VERSION 5.8 ;
BUSBITCHARS "[]" ;
DIVIDERCHAR "/" ;
UNITS
    DATABASE MICRONS 1000 ;
END UNITS

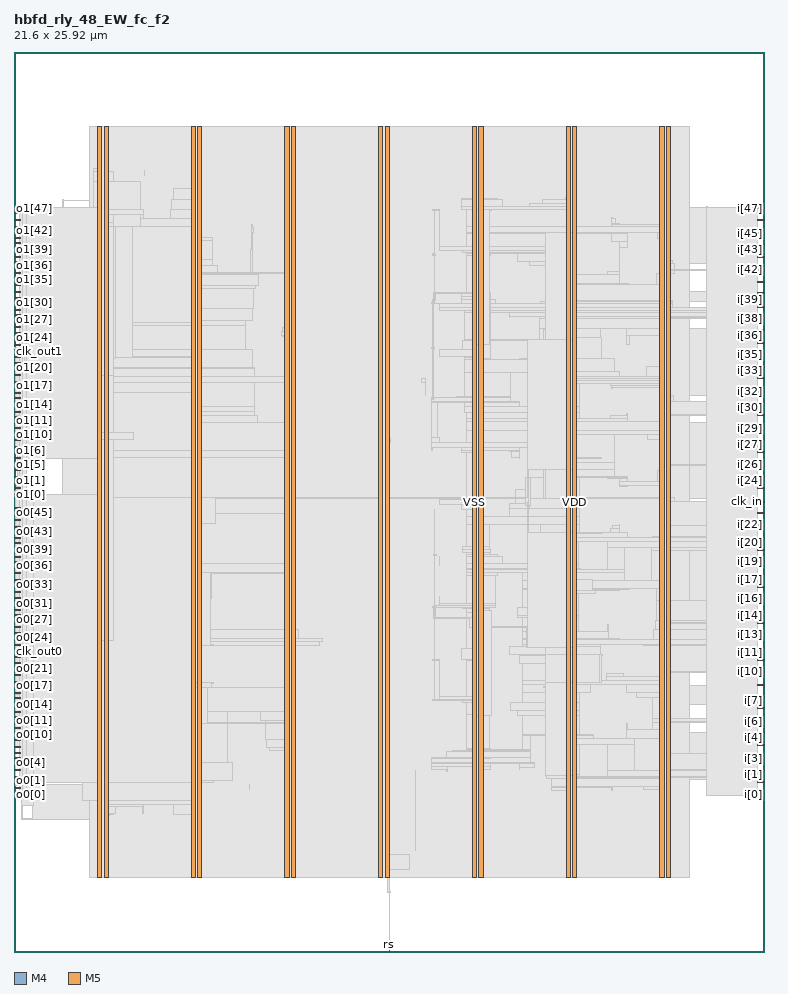
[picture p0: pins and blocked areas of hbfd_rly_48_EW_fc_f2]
MACRO hbfd_rly_48_EW_fc_f2
  FOREIGN hbfd_rly_48_EW_fc_f2 0 0 ;
  CLASS BLOCK ;
  SIZE 21.6 BY 25.92 ;
  PIN clk_in
    DIRECTION INPUT ;
    USE SIGNAL ;
    PORT
      LAYER M4 ;
        RECT  21.408 12.96 21.6 12.984 ;
    END
  END clk_in
  PIN clk_out0
    DIRECTION OUTPUT ;
    USE SIGNAL ;
    PORT
      LAYER M4 ;
        RECT  0 8.64 0.192 8.664 ;
    END
  END clk_out0
  PIN clk_out1
    DIRECTION OUTPUT ;
    USE SIGNAL ;
    PORT
      LAYER M4 ;
        RECT  0 17.28 0.192 17.304 ;
    END
  END clk_out1
  PIN i[0]
    DIRECTION INPUT ;
    USE SIGNAL ;
    PORT
      LAYER M4 ;
        RECT  21.408 4.512 21.6 4.536 ;
    END
  END i[0]
  PIN i[10]
    DIRECTION INPUT ;
    USE SIGNAL ;
    PORT
      LAYER M4 ;
        RECT  21.408 8.064 21.6 8.088 ;
    END
  END i[10]
  PIN i[11]
    DIRECTION INPUT ;
    USE SIGNAL ;
    PORT
      LAYER M4 ;
        RECT  21.408 8.4 21.6 8.424 ;
    END
  END i[11]
  PIN i[12]
    DIRECTION INPUT ;
    USE SIGNAL ;
    PORT
      LAYER M4 ;
        RECT  21.408 8.736 21.6 8.76 ;
    END
  END i[12]
  PIN i[13]
    DIRECTION INPUT ;
    USE SIGNAL ;
    PORT
      LAYER M4 ;
        RECT  21.408 9.12 21.6 9.144 ;
    END
  END i[13]
  PIN i[14]
    DIRECTION INPUT ;
    USE SIGNAL ;
    PORT
      LAYER M4 ;
        RECT  21.408 9.456 21.6 9.48 ;
    END
  END i[14]
  PIN i[15]
    DIRECTION INPUT ;
    USE SIGNAL ;
    PORT
      LAYER M4 ;
        RECT  21.408 9.792 21.6 9.816 ;
    END
  END i[15]
  PIN i[16]
    DIRECTION INPUT ;
    USE SIGNAL ;
    PORT
      LAYER M4 ;
        RECT  21.408 10.176 21.6 10.2 ;
    END
  END i[16]
  PIN i[17]
    DIRECTION INPUT ;
    USE SIGNAL ;
    PORT
      LAYER M4 ;
        RECT  21.408 10.512 21.6 10.536 ;
    END
  END i[17]
  PIN i[18]
    DIRECTION INPUT ;
    USE SIGNAL ;
    PORT
      LAYER M4 ;
        RECT  21.408 10.848 21.6 10.872 ;
    END
  END i[18]
  PIN i[19]
    DIRECTION INPUT ;
    USE SIGNAL ;
    PORT
      LAYER M4 ;
        RECT  21.408 11.232 21.6 11.256 ;
    END
  END i[19]
  PIN i[1]
    DIRECTION INPUT ;
    USE SIGNAL ;
    PORT
      LAYER M4 ;
        RECT  21.408 4.896 21.6 4.92 ;
    END
  END i[1]
  PIN i[20]
    DIRECTION INPUT ;
    USE SIGNAL ;
    PORT
      LAYER M4 ;
        RECT  21.408 11.568 21.6 11.592 ;
    END
  END i[20]
  PIN i[21]
    DIRECTION INPUT ;
    USE SIGNAL ;
    PORT
      LAYER M4 ;
        RECT  21.408 11.904 21.6 11.928 ;
    END
  END i[21]
  PIN i[22]
    DIRECTION INPUT ;
    USE SIGNAL ;
    PORT
      LAYER M4 ;
        RECT  21.408 12.288 21.6 12.312 ;
    END
  END i[22]
  PIN i[23]
    DIRECTION INPUT ;
    USE SIGNAL ;
    PORT
      LAYER M4 ;
        RECT  21.408 12.624 21.6 12.648 ;
    END
  END i[23]
  PIN i[24]
    DIRECTION INPUT ;
    USE SIGNAL ;
    PORT
      LAYER M4 ;
        RECT  21.408 13.344 21.6 13.368 ;
    END
  END i[24]
  PIN i[25]
    DIRECTION INPUT ;
    USE SIGNAL ;
    PORT
      LAYER M4 ;
        RECT  21.408 13.68 21.6 13.704 ;
    END
  END i[25]
  PIN i[26]
    DIRECTION INPUT ;
    USE SIGNAL ;
    PORT
      LAYER M4 ;
        RECT  21.408 14.016 21.6 14.04 ;
    END
  END i[26]
  PIN i[27]
    DIRECTION INPUT ;
    USE SIGNAL ;
    PORT
      LAYER M4 ;
        RECT  21.408 14.4 21.6 14.424 ;
    END
  END i[27]
  PIN i[28]
    DIRECTION INPUT ;
    USE SIGNAL ;
    PORT
      LAYER M4 ;
        RECT  21.408 14.736 21.6 14.76 ;
    END
  END i[28]
  PIN i[29]
    DIRECTION INPUT ;
    USE SIGNAL ;
    PORT
      LAYER M4 ;
        RECT  21.408 15.072 21.6 15.096 ;
    END
  END i[29]
  PIN i[2]
    DIRECTION INPUT ;
    USE SIGNAL ;
    PORT
      LAYER M4 ;
        RECT  21.408 5.232 21.6 5.256 ;
    END
  END i[2]
  PIN i[30]
    DIRECTION INPUT ;
    USE SIGNAL ;
    PORT
      LAYER M4 ;
        RECT  21.408 15.456 21.6 15.48 ;
    END
  END i[30]
  PIN i[31]
    DIRECTION INPUT ;
    USE SIGNAL ;
    PORT
      LAYER M4 ;
        RECT  21.408 15.792 21.6 15.816 ;
    END
  END i[31]
  PIN i[32]
    DIRECTION INPUT ;
    USE SIGNAL ;
    PORT
      LAYER M4 ;
        RECT  21.408 16.128 21.6 16.152 ;
    END
  END i[32]
  PIN i[33]
    DIRECTION INPUT ;
    USE SIGNAL ;
    PORT
      LAYER M4 ;
        RECT  21.408 16.512 21.6 16.536 ;
    END
  END i[33]
  PIN i[34]
    DIRECTION INPUT ;
    USE SIGNAL ;
    PORT
      LAYER M4 ;
        RECT  21.408 16.848 21.6 16.872 ;
    END
  END i[34]
  PIN i[35]
    DIRECTION INPUT ;
    USE SIGNAL ;
    PORT
      LAYER M4 ;
        RECT  21.408 17.184 21.6 17.208 ;
    END
  END i[35]
  PIN i[36]
    DIRECTION INPUT ;
    USE SIGNAL ;
    PORT
      LAYER M4 ;
        RECT  21.408 17.52 21.6 17.544 ;
    END
  END i[36]
  PIN i[37]
    DIRECTION INPUT ;
    USE SIGNAL ;
    PORT
      LAYER M4 ;
        RECT  21.408 17.904 21.6 17.928 ;
    END
  END i[37]
  PIN i[38]
    DIRECTION INPUT ;
    USE SIGNAL ;
    PORT
      LAYER M4 ;
        RECT  21.408 18.24 21.6 18.264 ;
    END
  END i[38]
  PIN i[39]
    DIRECTION INPUT ;
    USE SIGNAL ;
    PORT
      LAYER M4 ;
        RECT  21.408 18.576 21.6 18.6 ;
    END
  END i[39]
  PIN i[3]
    DIRECTION INPUT ;
    USE SIGNAL ;
    PORT
      LAYER M4 ;
        RECT  21.408 5.568 21.6 5.592 ;
    END
  END i[3]
  PIN i[40]
    DIRECTION INPUT ;
    USE SIGNAL ;
    PORT
      LAYER M4 ;
        RECT  21.408 18.96 21.6 18.984 ;
    END
  END i[40]
  PIN i[41]
    DIRECTION INPUT ;
    USE SIGNAL ;
    PORT
      LAYER M4 ;
        RECT  21.408 19.296 21.6 19.32 ;
    END
  END i[41]
  PIN i[42]
    DIRECTION INPUT ;
    USE SIGNAL ;
    PORT
      LAYER M4 ;
        RECT  21.408 19.632 21.6 19.656 ;
    END
  END i[42]
  PIN i[43]
    DIRECTION INPUT ;
    USE SIGNAL ;
    PORT
      LAYER M4 ;
        RECT  21.408 20.016 21.6 20.04 ;
    END
  END i[43]
  PIN i[44]
    DIRECTION INPUT ;
    USE SIGNAL ;
    PORT
      LAYER M4 ;
        RECT  21.408 20.352 21.6 20.376 ;
    END
  END i[44]
  PIN i[45]
    DIRECTION INPUT ;
    USE SIGNAL ;
    PORT
      LAYER M4 ;
        RECT  21.408 20.688 21.6 20.712 ;
    END
  END i[45]
  PIN i[46]
    DIRECTION INPUT ;
    USE SIGNAL ;
    PORT
      LAYER M4 ;
        RECT  21.408 21.072 21.6 21.096 ;
    END
  END i[46]
  PIN i[47]
    DIRECTION INPUT ;
    USE SIGNAL ;
    PORT
      LAYER M4 ;
        RECT  21.408 21.408 21.6 21.432 ;
    END
  END i[47]
  PIN i[4]
    DIRECTION INPUT ;
    USE SIGNAL ;
    PORT
      LAYER M4 ;
        RECT  21.408 5.952 21.6 5.976 ;
    END
  END i[4]
  PIN i[5]
    DIRECTION INPUT ;
    USE SIGNAL ;
    PORT
      LAYER M4 ;
        RECT  21.408 6.288 21.6 6.312 ;
    END
  END i[5]
  PIN i[6]
    DIRECTION INPUT ;
    USE SIGNAL ;
    PORT
      LAYER M4 ;
        RECT  21.408 6.624 21.6 6.648 ;
    END
  END i[6]
  PIN i[7]
    DIRECTION INPUT ;
    USE SIGNAL ;
    PORT
      LAYER M4 ;
        RECT  21.408 7.008 21.6 7.032 ;
    END
  END i[7]
  PIN i[8]
    DIRECTION INPUT ;
    USE SIGNAL ;
    PORT
      LAYER M4 ;
        RECT  21.408 7.344 21.6 7.368 ;
    END
  END i[8]
  PIN i[9]
    DIRECTION INPUT ;
    USE SIGNAL ;
    PORT
      LAYER M4 ;
        RECT  21.408 7.68 21.6 7.704 ;
    END
  END i[9]
  PIN o0[0]
    DIRECTION OUTPUT ;
    USE SIGNAL ;
    PORT
      LAYER M4 ;
        RECT  0 4.512 0.192 4.536 ;
    END
  END o0[0]
  PIN o0[10]
    DIRECTION OUTPUT ;
    USE SIGNAL ;
    PORT
      LAYER M4 ;
        RECT  0 6.24 0.192 6.264 ;
    END
  END o0[10]
  PIN o0[11]
    DIRECTION OUTPUT ;
    USE SIGNAL ;
    PORT
      LAYER M4 ;
        RECT  0 6.432 0.192 6.456 ;
    END
  END o0[11]
  PIN o0[12]
    DIRECTION OUTPUT ;
    USE SIGNAL ;
    PORT
      LAYER M4 ;
        RECT  0 6.576 0.192 6.6 ;
    END
  END o0[12]
  PIN o0[13]
    DIRECTION OUTPUT ;
    USE SIGNAL ;
    PORT
      LAYER M4 ;
        RECT  0 6.768 0.192 6.792 ;
    END
  END o0[13]
  PIN o0[14]
    DIRECTION OUTPUT ;
    USE SIGNAL ;
    PORT
      LAYER M4 ;
        RECT  0 6.912 0.192 6.936 ;
    END
  END o0[14]
  PIN o0[15]
    DIRECTION OUTPUT ;
    USE SIGNAL ;
    PORT
      LAYER M4 ;
        RECT  0 7.104 0.192 7.128 ;
    END
  END o0[15]
  PIN o0[16]
    DIRECTION OUTPUT ;
    USE SIGNAL ;
    PORT
      LAYER M4 ;
        RECT  0 7.296 0.192 7.32 ;
    END
  END o0[16]
  PIN o0[17]
    DIRECTION OUTPUT ;
    USE SIGNAL ;
    PORT
      LAYER M4 ;
        RECT  0 7.44 0.192 7.464 ;
    END
  END o0[17]
  PIN o0[18]
    DIRECTION OUTPUT ;
    USE SIGNAL ;
    PORT
      LAYER M4 ;
        RECT  0 7.632 0.192 7.656 ;
    END
  END o0[18]
  PIN o0[19]
    DIRECTION OUTPUT ;
    USE SIGNAL ;
    PORT
      LAYER M4 ;
        RECT  0 7.776 0.192 7.8 ;
    END
  END o0[19]
  PIN o0[1]
    DIRECTION OUTPUT ;
    USE SIGNAL ;
    PORT
      LAYER M4 ;
        RECT  0 4.704 0.192 4.728 ;
    END
  END o0[1]
  PIN o0[20]
    DIRECTION OUTPUT ;
    USE SIGNAL ;
    PORT
      LAYER M4 ;
        RECT  0 7.968 0.192 7.992 ;
    END
  END o0[20]
  PIN o0[21]
    DIRECTION OUTPUT ;
    USE SIGNAL ;
    PORT
      LAYER M4 ;
        RECT  0 8.16 0.192 8.184 ;
    END
  END o0[21]
  PIN o0[22]
    DIRECTION OUTPUT ;
    USE SIGNAL ;
    PORT
      LAYER M4 ;
        RECT  0 8.304 0.192 8.328 ;
    END
  END o0[22]
  PIN o0[23]
    DIRECTION OUTPUT ;
    USE SIGNAL ;
    PORT
      LAYER M4 ;
        RECT  0 8.496 0.192 8.52 ;
    END
  END o0[23]
  PIN o0[24]
    DIRECTION OUTPUT ;
    USE SIGNAL ;
    PORT
      LAYER M4 ;
        RECT  0 8.832 0.192 8.856 ;
    END
  END o0[24]
  PIN o0[25]
    DIRECTION OUTPUT ;
    USE SIGNAL ;
    PORT
      LAYER M4 ;
        RECT  0 8.976 0.192 9 ;
    END
  END o0[25]
  PIN o0[26]
    DIRECTION OUTPUT ;
    USE SIGNAL ;
    PORT
      LAYER M4 ;
        RECT  0 9.168 0.192 9.192 ;
    END
  END o0[26]
  PIN o0[27]
    DIRECTION OUTPUT ;
    USE SIGNAL ;
    PORT
      LAYER M4 ;
        RECT  0 9.36 0.192 9.384 ;
    END
  END o0[27]
  PIN o0[28]
    DIRECTION OUTPUT ;
    USE SIGNAL ;
    PORT
      LAYER M4 ;
        RECT  0 9.504 0.192 9.528 ;
    END
  END o0[28]
  PIN o0[29]
    DIRECTION OUTPUT ;
    USE SIGNAL ;
    PORT
      LAYER M4 ;
        RECT  0 9.696 0.192 9.72 ;
    END
  END o0[29]
  PIN o0[2]
    DIRECTION OUTPUT ;
    USE SIGNAL ;
    PORT
      LAYER M4 ;
        RECT  0 4.896 0.192 4.92 ;
    END
  END o0[2]
  PIN o0[30]
    DIRECTION OUTPUT ;
    USE SIGNAL ;
    PORT
      LAYER M4 ;
        RECT  0 9.84 0.192 9.864 ;
    END
  END o0[30]
  PIN o0[31]
    DIRECTION OUTPUT ;
    USE SIGNAL ;
    PORT
      LAYER M4 ;
        RECT  0 10.032 0.192 10.056 ;
    END
  END o0[31]
  PIN o0[32]
    DIRECTION OUTPUT ;
    USE SIGNAL ;
    PORT
      LAYER M4 ;
        RECT  0 10.176 0.192 10.2 ;
    END
  END o0[32]
  PIN o0[33]
    DIRECTION OUTPUT ;
    USE SIGNAL ;
    PORT
      LAYER M4 ;
        RECT  0 10.368 0.192 10.392 ;
    END
  END o0[33]
  PIN o0[34]
    DIRECTION OUTPUT ;
    USE SIGNAL ;
    PORT
      LAYER M4 ;
        RECT  0 10.56 0.192 10.584 ;
    END
  END o0[34]
  PIN o0[35]
    DIRECTION OUTPUT ;
    USE SIGNAL ;
    PORT
      LAYER M4 ;
        RECT  0 10.704 0.192 10.728 ;
    END
  END o0[35]
  PIN o0[36]
    DIRECTION OUTPUT ;
    USE SIGNAL ;
    PORT
      LAYER M4 ;
        RECT  0 10.896 0.192 10.92 ;
    END
  END o0[36]
  PIN o0[37]
    DIRECTION OUTPUT ;
    USE SIGNAL ;
    PORT
      LAYER M4 ;
        RECT  0 11.04 0.192 11.064 ;
    END
  END o0[37]
  PIN o0[38]
    DIRECTION OUTPUT ;
    USE SIGNAL ;
    PORT
      LAYER M4 ;
        RECT  0 11.232 0.192 11.256 ;
    END
  END o0[38]
  PIN o0[39]
    DIRECTION OUTPUT ;
    USE SIGNAL ;
    PORT
      LAYER M4 ;
        RECT  0 11.376 0.192 11.4 ;
    END
  END o0[39]
  PIN o0[3]
    DIRECTION OUTPUT ;
    USE SIGNAL ;
    PORT
      LAYER M4 ;
        RECT  0 5.04 0.192 5.064 ;
    END
  END o0[3]
  PIN o0[40]
    DIRECTION OUTPUT ;
    USE SIGNAL ;
    PORT
      LAYER M4 ;
        RECT  0 11.568 0.192 11.592 ;
    END
  END o0[40]
  PIN o0[41]
    DIRECTION OUTPUT ;
    USE SIGNAL ;
    PORT
      LAYER M4 ;
        RECT  0 11.76 0.192 11.784 ;
    END
  END o0[41]
  PIN o0[42]
    DIRECTION OUTPUT ;
    USE SIGNAL ;
    PORT
      LAYER M4 ;
        RECT  0 11.904 0.192 11.928 ;
    END
  END o0[42]
  PIN o0[43]
    DIRECTION OUTPUT ;
    USE SIGNAL ;
    PORT
      LAYER M4 ;
        RECT  0 12.096 0.192 12.12 ;
    END
  END o0[43]
  PIN o0[44]
    DIRECTION OUTPUT ;
    USE SIGNAL ;
    PORT
      LAYER M4 ;
        RECT  0 12.24 0.192 12.264 ;
    END
  END o0[44]
  PIN o0[45]
    DIRECTION OUTPUT ;
    USE SIGNAL ;
    PORT
      LAYER M4 ;
        RECT  0 12.432 0.192 12.456 ;
    END
  END o0[45]
  PIN o0[46]
    DIRECTION OUTPUT ;
    USE SIGNAL ;
    PORT
      LAYER M4 ;
        RECT  0 12.624 0.192 12.648 ;
    END
  END o0[46]
  PIN o0[47]
    DIRECTION OUTPUT ;
    USE SIGNAL ;
    PORT
      LAYER M4 ;
        RECT  0 12.768 0.192 12.792 ;
    END
  END o0[47]
  PIN o0[4]
    DIRECTION OUTPUT ;
    USE SIGNAL ;
    PORT
      LAYER M4 ;
        RECT  0 5.232 0.192 5.256 ;
    END
  END o0[4]
  PIN o0[5]
    DIRECTION OUTPUT ;
    USE SIGNAL ;
    PORT
      LAYER M4 ;
        RECT  0 5.376 0.192 5.4 ;
    END
  END o0[5]
  PIN o0[6]
    DIRECTION OUTPUT ;
    USE SIGNAL ;
    PORT
      LAYER M4 ;
        RECT  0 5.568 0.192 5.592 ;
    END
  END o0[6]
  PIN o0[7]
    DIRECTION OUTPUT ;
    USE SIGNAL ;
    PORT
      LAYER M4 ;
        RECT  0 5.712 0.192 5.736 ;
    END
  END o0[7]
  PIN o0[8]
    DIRECTION OUTPUT ;
    USE SIGNAL ;
    PORT
      LAYER M4 ;
        RECT  0 5.904 0.192 5.928 ;
    END
  END o0[8]
  PIN o0[9]
    DIRECTION OUTPUT ;
    USE SIGNAL ;
    PORT
      LAYER M4 ;
        RECT  0 6.096 0.192 6.12 ;
    END
  END o0[9]
  PIN o1[0]
    DIRECTION OUTPUT ;
    USE SIGNAL ;
    PORT
      LAYER M4 ;
        RECT  0 13.152 0.192 13.176 ;
    END
  END o1[0]
  PIN o1[10]
    DIRECTION OUTPUT ;
    USE SIGNAL ;
    PORT
      LAYER M4 ;
        RECT  0 14.88 0.192 14.904 ;
    END
  END o1[10]
  PIN o1[11]
    DIRECTION OUTPUT ;
    USE SIGNAL ;
    PORT
      LAYER M4 ;
        RECT  0 15.072 0.192 15.096 ;
    END
  END o1[11]
  PIN o1[12]
    DIRECTION OUTPUT ;
    USE SIGNAL ;
    PORT
      LAYER M4 ;
        RECT  0 15.216 0.192 15.24 ;
    END
  END o1[12]
  PIN o1[13]
    DIRECTION OUTPUT ;
    USE SIGNAL ;
    PORT
      LAYER M4 ;
        RECT  0 15.408 0.192 15.432 ;
    END
  END o1[13]
  PIN o1[14]
    DIRECTION OUTPUT ;
    USE SIGNAL ;
    PORT
      LAYER M4 ;
        RECT  0 15.552 0.192 15.576 ;
    END
  END o1[14]
  PIN o1[15]
    DIRECTION OUTPUT ;
    USE SIGNAL ;
    PORT
      LAYER M4 ;
        RECT  0 15.744 0.192 15.768 ;
    END
  END o1[15]
  PIN o1[16]
    DIRECTION OUTPUT ;
    USE SIGNAL ;
    PORT
      LAYER M4 ;
        RECT  0 15.936 0.192 15.96 ;
    END
  END o1[16]
  PIN o1[17]
    DIRECTION OUTPUT ;
    USE SIGNAL ;
    PORT
      LAYER M4 ;
        RECT  0 16.08 0.192 16.104 ;
    END
  END o1[17]
  PIN o1[18]
    DIRECTION OUTPUT ;
    USE SIGNAL ;
    PORT
      LAYER M4 ;
        RECT  0 16.272 0.192 16.296 ;
    END
  END o1[18]
  PIN o1[19]
    DIRECTION OUTPUT ;
    USE SIGNAL ;
    PORT
      LAYER M4 ;
        RECT  0 16.416 0.192 16.44 ;
    END
  END o1[19]
  PIN o1[1]
    DIRECTION OUTPUT ;
    USE SIGNAL ;
    PORT
      LAYER M4 ;
        RECT  0 13.344 0.192 13.368 ;
    END
  END o1[1]
  PIN o1[20]
    DIRECTION OUTPUT ;
    USE SIGNAL ;
    PORT
      LAYER M4 ;
        RECT  0 16.608 0.192 16.632 ;
    END
  END o1[20]
  PIN o1[21]
    DIRECTION OUTPUT ;
    USE SIGNAL ;
    PORT
      LAYER M4 ;
        RECT  0 16.8 0.192 16.824 ;
    END
  END o1[21]
  PIN o1[22]
    DIRECTION OUTPUT ;
    USE SIGNAL ;
    PORT
      LAYER M4 ;
        RECT  0 16.944 0.192 16.968 ;
    END
  END o1[22]
  PIN o1[23]
    DIRECTION OUTPUT ;
    USE SIGNAL ;
    PORT
      LAYER M4 ;
        RECT  0 17.136 0.192 17.16 ;
    END
  END o1[23]
  PIN o1[24]
    DIRECTION OUTPUT ;
    USE SIGNAL ;
    PORT
      LAYER M4 ;
        RECT  0 17.472 0.192 17.496 ;
    END
  END o1[24]
  PIN o1[25]
    DIRECTION OUTPUT ;
    USE SIGNAL ;
    PORT
      LAYER M4 ;
        RECT  0 17.616 0.192 17.64 ;
    END
  END o1[25]
  PIN o1[26]
    DIRECTION OUTPUT ;
    USE SIGNAL ;
    PORT
      LAYER M4 ;
        RECT  0 17.808 0.192 17.832 ;
    END
  END o1[26]
  PIN o1[27]
    DIRECTION OUTPUT ;
    USE SIGNAL ;
    PORT
      LAYER M4 ;
        RECT  0 18 0.192 18.024 ;
    END
  END o1[27]
  PIN o1[28]
    DIRECTION OUTPUT ;
    USE SIGNAL ;
    PORT
      LAYER M4 ;
        RECT  0 18.144 0.192 18.168 ;
    END
  END o1[28]
  PIN o1[29]
    DIRECTION OUTPUT ;
    USE SIGNAL ;
    PORT
      LAYER M4 ;
        RECT  0 18.336 0.192 18.36 ;
    END
  END o1[29]
  PIN o1[2]
    DIRECTION OUTPUT ;
    USE SIGNAL ;
    PORT
      LAYER M4 ;
        RECT  0 13.536 0.192 13.56 ;
    END
  END o1[2]
  PIN o1[30]
    DIRECTION OUTPUT ;
    USE SIGNAL ;
    PORT
      LAYER M4 ;
        RECT  0 18.48 0.192 18.504 ;
    END
  END o1[30]
  PIN o1[31]
    DIRECTION OUTPUT ;
    USE SIGNAL ;
    PORT
      LAYER M4 ;
        RECT  0 18.672 0.192 18.696 ;
    END
  END o1[31]
  PIN o1[32]
    DIRECTION OUTPUT ;
    USE SIGNAL ;
    PORT
      LAYER M4 ;
        RECT  0 18.816 0.192 18.84 ;
    END
  END o1[32]
  PIN o1[33]
    DIRECTION OUTPUT ;
    USE SIGNAL ;
    PORT
      LAYER M4 ;
        RECT  0 19.008 0.192 19.032 ;
    END
  END o1[33]
  PIN o1[34]
    DIRECTION OUTPUT ;
    USE SIGNAL ;
    PORT
      LAYER M4 ;
        RECT  0 19.2 0.192 19.224 ;
    END
  END o1[34]
  PIN o1[35]
    DIRECTION OUTPUT ;
    USE SIGNAL ;
    PORT
      LAYER M4 ;
        RECT  0 19.344 0.192 19.368 ;
    END
  END o1[35]
  PIN o1[36]
    DIRECTION OUTPUT ;
    USE SIGNAL ;
    PORT
      LAYER M4 ;
        RECT  0 19.536 0.192 19.56 ;
    END
  END o1[36]
  PIN o1[37]
    DIRECTION OUTPUT ;
    USE SIGNAL ;
    PORT
      LAYER M4 ;
        RECT  0 19.68 0.192 19.704 ;
    END
  END o1[37]
  PIN o1[38]
    DIRECTION OUTPUT ;
    USE SIGNAL ;
    PORT
      LAYER M4 ;
        RECT  0 19.872 0.192 19.896 ;
    END
  END o1[38]
  PIN o1[39]
    DIRECTION OUTPUT ;
    USE SIGNAL ;
    PORT
      LAYER M4 ;
        RECT  0 20.016 0.192 20.04 ;
    END
  END o1[39]
  PIN o1[3]
    DIRECTION OUTPUT ;
    USE SIGNAL ;
    PORT
      LAYER M4 ;
        RECT  0 13.68 0.192 13.704 ;
    END
  END o1[3]
  PIN o1[40]
    DIRECTION OUTPUT ;
    USE SIGNAL ;
    PORT
      LAYER M4 ;
        RECT  0 20.208 0.192 20.232 ;
    END
  END o1[40]
  PIN o1[41]
    DIRECTION OUTPUT ;
    USE SIGNAL ;
    PORT
      LAYER M4 ;
        RECT  0 20.4 0.192 20.424 ;
    END
  END o1[41]
  PIN o1[42]
    DIRECTION OUTPUT ;
    USE SIGNAL ;
    PORT
      LAYER M4 ;
        RECT  0 20.544 0.192 20.568 ;
    END
  END o1[42]
  PIN o1[43]
    DIRECTION OUTPUT ;
    USE SIGNAL ;
    PORT
      LAYER M4 ;
        RECT  0 20.736 0.192 20.76 ;
    END
  END o1[43]
  PIN o1[44]
    DIRECTION OUTPUT ;
    USE SIGNAL ;
    PORT
      LAYER M4 ;
        RECT  0 20.88 0.192 20.904 ;
    END
  END o1[44]
  PIN o1[45]
    DIRECTION OUTPUT ;
    USE SIGNAL ;
    PORT
      LAYER M4 ;
        RECT  0 21.072 0.192 21.096 ;
    END
  END o1[45]
  PIN o1[46]
    DIRECTION OUTPUT ;
    USE SIGNAL ;
    PORT
      LAYER M4 ;
        RECT  0 21.264 0.192 21.288 ;
    END
  END o1[46]
  PIN o1[47]
    DIRECTION OUTPUT ;
    USE SIGNAL ;
    PORT
      LAYER M4 ;
        RECT  0 21.408 0.192 21.432 ;
    END
  END o1[47]
  PIN o1[4]
    DIRECTION OUTPUT ;
    USE SIGNAL ;
    PORT
      LAYER M4 ;
        RECT  0 13.872 0.192 13.896 ;
    END
  END o1[4]
  PIN o1[5]
    DIRECTION OUTPUT ;
    USE SIGNAL ;
    PORT
      LAYER M4 ;
        RECT  0 14.016 0.192 14.04 ;
    END
  END o1[5]
  PIN o1[6]
    DIRECTION OUTPUT ;
    USE SIGNAL ;
    PORT
      LAYER M4 ;
        RECT  0 14.208 0.192 14.232 ;
    END
  END o1[6]
  PIN o1[7]
    DIRECTION OUTPUT ;
    USE SIGNAL ;
    PORT
      LAYER M4 ;
        RECT  0 14.352 0.192 14.376 ;
    END
  END o1[7]
  PIN o1[8]
    DIRECTION OUTPUT ;
    USE SIGNAL ;
    PORT
      LAYER M4 ;
        RECT  0 14.544 0.192 14.568 ;
    END
  END o1[8]
  PIN o1[9]
    DIRECTION OUTPUT ;
    USE SIGNAL ;
    PORT
      LAYER M4 ;
        RECT  0 14.736 0.192 14.76 ;
    END
  END o1[9]
  PIN rs
    DIRECTION INPUT ;
    USE SIGNAL ;
    PORT
      LAYER M5 ;
        RECT  10.8 0 10.824 0.192 ;
    END
  END rs
  PIN VDD
    DIRECTION INOUT ;
    USE POWER ;
    PORT
      LAYER M5 ;
        RECT  18.792 2.151 18.912 23.769 ;
        RECT  16.092 2.151 16.212 23.769 ;
        RECT  13.392 2.151 13.512 23.769 ;
        RECT  10.692 2.151 10.812 23.769 ;
        RECT  7.992 2.151 8.112 23.769 ;
        RECT  5.292 2.151 5.412 23.769 ;
        RECT  2.592 2.151 2.712 23.769 ;
    END
  END VDD
  PIN VSS
    DIRECTION INOUT ;
    USE GROUND ;
    PORT
      LAYER M5 ;
        RECT  18.6 2.137 18.72 23.783 ;
        RECT  15.9 2.137 16.02 23.783 ;
        RECT  13.2 2.137 13.32 23.783 ;
        RECT  10.5 2.137 10.62 23.783 ;
        RECT  7.8 2.137 7.92 23.783 ;
        RECT  5.1 2.137 5.22 23.783 ;
        RECT  2.4 2.137 2.52 23.783 ;
    END
  END VSS
  OBS
    LAYER RVTN ;
     RECT  2.16 2.16 19.44 2.295 ;
     RECT  2.16 2.565 19.44 2.835 ;
     RECT  2.16 3.105 19.44 3.375 ;
     RECT  2.16 3.645 19.44 3.915 ;
     RECT  2.16 4.185 19.44 4.455 ;
     RECT  2.16 4.725 19.44 4.995 ;
     RECT  2.16 5.265 19.44 5.535 ;
     RECT  2.16 5.805 19.44 6.075 ;
     RECT  2.16 6.345 19.44 6.615 ;
     RECT  2.16 6.885 19.44 7.155 ;
     RECT  2.16 7.425 19.44 7.695 ;
     RECT  2.16 7.965 19.44 8.235 ;
     RECT  2.16 8.505 19.44 8.775 ;
     RECT  2.16 9.045 19.44 9.315 ;
     RECT  2.16 9.585 19.44 9.855 ;
     RECT  2.16 10.125 19.44 10.395 ;
     RECT  2.16 10.665 19.44 10.935 ;
     RECT  2.16 11.205 19.44 11.475 ;
     RECT  2.16 11.745 19.44 12.015 ;
     RECT  2.16 12.285 19.44 12.555 ;
     RECT  2.16 12.825 19.44 13.095 ;
     RECT  2.16 13.365 19.44 13.635 ;
     RECT  2.16 13.905 19.44 14.175 ;
     RECT  2.16 14.445 19.44 14.715 ;
     RECT  2.16 14.985 19.44 15.255 ;
     RECT  2.16 15.525 19.44 15.795 ;
     RECT  2.16 16.065 19.44 16.335 ;
     RECT  2.16 16.605 19.44 16.875 ;
     RECT  2.16 17.145 19.44 17.415 ;
     RECT  2.16 17.685 19.44 17.955 ;
     RECT  2.16 18.225 19.44 18.495 ;
     RECT  2.16 18.765 19.44 19.035 ;
     RECT  2.16 19.305 19.44 19.575 ;
     RECT  2.16 19.845 19.44 20.115 ;
     RECT  2.16 20.385 19.44 20.655 ;
     RECT  2.16 20.925 19.44 21.195 ;
     RECT  2.16 21.465 19.44 21.735 ;
     RECT  2.16 22.005 19.44 22.275 ;
     RECT  2.16 22.545 19.44 22.815 ;
     RECT  2.16 23.085 19.44 23.355 ;
     RECT  2.16 23.625 19.44 23.76 ;
    LAYER RVTP ;
     RECT  2.16 2.295 19.44 2.565 ;
     RECT  2.16 2.835 19.44 3.105 ;
     RECT  2.16 3.375 19.44 3.645 ;
     RECT  2.16 3.915 19.44 4.185 ;
     RECT  2.16 4.455 19.44 4.725 ;
     RECT  2.16 4.995 19.44 5.265 ;
     RECT  2.16 5.535 19.44 5.805 ;
     RECT  2.16 6.075 19.44 6.345 ;
     RECT  2.16 6.615 19.44 6.885 ;
     RECT  2.16 7.155 19.44 7.425 ;
     RECT  2.16 7.695 19.44 7.965 ;
     RECT  2.16 8.235 19.44 8.505 ;
     RECT  2.16 8.775 19.44 9.045 ;
     RECT  2.16 9.315 19.44 9.585 ;
     RECT  2.16 9.855 19.44 10.125 ;
     RECT  2.16 10.395 19.44 10.665 ;
     RECT  2.16 10.935 19.44 11.205 ;
     RECT  2.16 11.475 19.44 11.745 ;
     RECT  2.16 12.015 19.44 12.285 ;
     RECT  2.16 12.555 19.44 12.825 ;
     RECT  2.16 13.095 19.44 13.365 ;
     RECT  2.16 13.635 19.44 13.905 ;
     RECT  2.16 14.175 19.44 14.445 ;
     RECT  2.16 14.715 19.44 14.985 ;
     RECT  2.16 15.255 19.44 15.525 ;
     RECT  2.16 15.795 19.44 16.065 ;
     RECT  2.16 16.335 19.44 16.605 ;
     RECT  2.16 16.875 19.44 17.145 ;
     RECT  2.16 17.415 19.44 17.685 ;
     RECT  2.16 17.955 19.44 18.225 ;
     RECT  2.16 18.495 19.44 18.765 ;
     RECT  2.16 19.035 19.44 19.305 ;
     RECT  2.16 19.575 19.44 19.845 ;
     RECT  2.16 20.115 19.44 20.385 ;
     RECT  2.16 20.655 19.44 20.925 ;
     RECT  2.16 21.195 19.44 21.465 ;
     RECT  2.16 21.735 19.44 22.005 ;
     RECT  2.16 22.275 19.44 22.545 ;
     RECT  2.16 22.815 19.44 23.085 ;
     RECT  2.16 23.355 19.44 23.625 ;
    LAYER M1 ;
     RECT  2.16 2.151 19.44 23.769 ;
    LAYER M2 ;
     RECT  0.067 13.608 0.103 13.626 ;
     RECT  0.031 14.454 0.103 14.472 ;
     RECT  0.067 6.246 0.139 6.264 ;
     RECT  0.103 13.608 0.239 14.472 ;
     RECT  0.247 17.424 0.283 17.442 ;
     RECT  0.211 20.196 0.311 20.214 ;
     RECT  0.283 12.456 0.383 12.546 ;
     RECT  0.283 17.424 0.463 18.144 ;
     RECT  0.211 3.816 0.535 3.834 ;
     RECT  0.031 4.806 0.535 4.824 ;
     RECT  0.239 14.454 0.535 14.472 ;
     RECT  0.499 15.336 0.535 15.354 ;
     RECT  0.463 16.506 0.535 18.144 ;
     RECT  0.383 12.528 1.507 12.546 ;
     RECT  1.435 13.536 1.507 13.554 ;
     RECT  0.103 8.478 2.011 8.496 ;
     RECT  0.535 3.816 2.16 4.824 ;
     RECT  0.139 6.12 2.16 6.264 ;
     RECT  0.175 7.362 2.16 7.38 ;
     RECT  2.011 8.316 2.16 8.496 ;
     RECT  0.319 9.558 2.16 9.576 ;
     RECT  1.723 10.368 2.16 11.196 ;
     RECT  1.507 12.528 2.16 13.554 ;
     RECT  0.535 14.454 2.16 15.354 ;
     RECT  0.535 16.236 2.16 18.144 ;
     RECT  0.535 19.35 2.16 19.368 ;
     RECT  0.535 20.43 2.16 20.448 ;
     RECT  1.399 21.636 2.16 21.654 ;
     RECT  2.16 2.151 19.44 23.769 ;
     RECT  19.44 4.968 19.967 6.336 ;
     RECT  19.44 7.128 19.967 7.686 ;
     RECT  19.44 8.478 19.967 11.97 ;
     RECT  19.44 13.068 19.967 15.246 ;
     RECT  19.44 16.038 19.967 17.946 ;
     RECT  19.44 18.738 19.967 19.026 ;
     RECT  19.44 19.818 19.967 21.456 ;
     RECT  19.967 4.968 20.003 4.986 ;
     RECT  19.967 10.98 20.543 10.998 ;
     RECT  19.967 21.24 20.543 21.258 ;
    LAYER M3 ;
     RECT  10.8 1.723 10.818 2.143 ;
     RECT  10.515 2.143 10.818 2.371 ;
     RECT  2.415 2.143 2.505 2.413 ;
     RECT  5.115 2.143 5.205 2.413 ;
     RECT  7.815 2.143 7.905 2.413 ;
     RECT  13.215 2.143 13.305 2.413 ;
     RECT  15.915 2.143 16.005 2.413 ;
     RECT  18.615 2.143 18.705 2.413 ;
     RECT  10.515 2.371 11.394 2.795 ;
     RECT  2.415 2.413 2.697 3.919 ;
     RECT  2.415 3.919 2.754 3.955 ;
     RECT  5.115 2.413 5.397 3.955 ;
     RECT  2.415 3.955 2.862 3.991 ;
     RECT  2.415 3.991 2.934 4.189 ;
     RECT  3.708 3.991 3.726 4.189 ;
     RECT  0.216 3.811 0.234 4.225 ;
     RECT  2.415 4.189 3.726 4.261 ;
     RECT  4.608 3.955 5.397 4.261 ;
     RECT  2.415 4.261 5.397 4.351 ;
     RECT  15.915 2.413 16.197 4.657 ;
     RECT  18.615 2.413 18.897 4.693 ;
     RECT  15.48 4.657 16.197 4.729 ;
     RECT  17.208 4.657 17.226 4.729 ;
     RECT  0.216 4.225 0.558 4.733 ;
     RECT  15.48 4.729 17.226 4.765 ;
     RECT  18.144 4.693 18.897 4.765 ;
     RECT  6.768 4.693 6.786 4.829 ;
     RECT  1.98 4.351 5.397 4.891 ;
     RECT  19.944 4.507 19.962 4.891 ;
     RECT  1.98 4.891 5.742 4.927 ;
     RECT  15.48 4.765 18.897 4.987 ;
     RECT  19.944 4.891 19.998 4.991 ;
     RECT  15.336 4.987 18.897 5.035 ;
     RECT  19.944 4.991 19.962 5.035 ;
     RECT  15.336 5.035 19.962 5.063 ;
     RECT  15.336 5.063 16.29 5.117 ;
     RECT  11.556 2.911 11.574 5.225 ;
     RECT  17.1 5.063 19.962 5.225 ;
     RECT  12.456 5.197 12.474 5.269 ;
     RECT  13.215 2.413 13.497 5.269 ;
     RECT  14.544 5.269 14.562 5.305 ;
     RECT  12.024 5.269 12.474 5.341 ;
     RECT  13.215 5.269 13.734 5.341 ;
     RECT  12.024 5.341 13.734 5.431 ;
     RECT  14.544 5.305 14.994 5.431 ;
     RECT  1.98 4.927 6.282 5.459 ;
     RECT  12.024 5.431 14.994 5.459 ;
     RECT  12.024 5.459 14.886 5.603 ;
     RECT  18.615 5.225 19.962 5.729 ;
     RECT  12.456 5.603 14.886 5.765 ;
     RECT  12.636 5.765 14.886 5.801 ;
     RECT  7.815 2.413 8.097 5.809 ;
     RECT  13.032 5.801 14.886 5.837 ;
     RECT  13.032 5.837 13.734 5.873 ;
     RECT  7.344 5.809 8.097 5.881 ;
     RECT  0.036 4.801 0.054 5.899 ;
     RECT  15.915 5.117 16.29 5.971 ;
     RECT  17.1 5.225 17.874 5.971 ;
     RECT  7.272 5.881 8.097 6.115 ;
     RECT  15.915 5.971 17.874 6.143 ;
     RECT  17.64 6.143 17.874 6.151 ;
     RECT  18.615 5.729 18.897 6.151 ;
     RECT  14.652 5.837 14.886 6.235 ;
     RECT  15.915 6.143 16.686 6.235 ;
     RECT  14.652 6.235 16.686 6.269 ;
     RECT  17.64 6.151 18.897 6.413 ;
     RECT  0.036 5.899 0.27 6.427 ;
     RECT  17.64 6.413 17.658 6.575 ;
     RECT  18.396 6.413 18.897 6.619 ;
     RECT  19.944 5.729 19.962 6.619 ;
     RECT  7.236 6.115 8.097 6.655 ;
     RECT  18.396 6.619 19.962 6.719 ;
     RECT  14.652 6.269 16.29 6.817 ;
     RECT  13.032 5.873 13.698 6.845 ;
     RECT  1.98 5.459 6.138 6.925 ;
     RECT  7.092 6.655 8.097 6.925 ;
     RECT  14.508 6.817 16.29 6.961 ;
     RECT  14.292 6.961 16.29 7.187 ;
     RECT  13.032 6.845 13.497 7.195 ;
     RECT  12.924 7.195 13.497 7.231 ;
     RECT  12.096 7.231 13.497 7.277 ;
     RECT  18.396 6.719 18.897 7.321 ;
     RECT  12.24 7.277 13.497 7.349 ;
     RECT  0.036 6.427 0.306 7.421 ;
     RECT  14.652 7.187 16.29 7.465 ;
     RECT  17.928 7.321 18.897 7.465 ;
     RECT  1.98 6.925 8.097 7.627 ;
     RECT  14.652 7.465 16.614 7.699 ;
     RECT  17.64 7.465 18.897 7.699 ;
     RECT  14.652 7.699 18.897 7.805 ;
     RECT  17.064 7.805 18.897 7.925 ;
     RECT  17.064 7.925 17.55 8.033 ;
     RECT  18.615 7.925 18.897 8.059 ;
     RECT  19.944 6.719 19.962 8.059 ;
     RECT  14.652 7.805 16.29 8.311 ;
     RECT  12.24 7.349 12.258 8.395 ;
     RECT  13.032 7.349 13.497 8.395 ;
     RECT  12.096 8.395 12.258 8.429 ;
     RECT  12.096 8.429 12.114 8.435 ;
     RECT  13.032 8.395 13.734 8.435 ;
     RECT  13.032 8.435 13.497 8.437 ;
     RECT  14.544 8.311 16.29 8.539 ;
     RECT  14.544 8.539 16.902 8.581 ;
     RECT  12.888 8.437 13.497 8.735 ;
     RECT  14.256 8.581 16.902 8.807 ;
     RECT  1.728 7.627 8.097 8.815 ;
     RECT  18.615 8.059 19.962 8.815 ;
     RECT  14.652 8.807 16.902 8.851 ;
     RECT  18.144 8.815 19.962 8.851 ;
     RECT  1.728 8.815 8.802 8.941 ;
     RECT  0.036 7.421 0.198 8.971 ;
     RECT  14.652 8.851 19.962 9.005 ;
     RECT  1.728 8.941 8.874 9.041 ;
     RECT  14.652 9.005 17.442 9.041 ;
     RECT  14.652 9.041 17.118 9.239 ;
     RECT  1.728 9.041 8.19 9.275 ;
     RECT  18.432 9.005 19.962 9.275 ;
     RECT  17.1 9.239 17.118 9.419 ;
     RECT  18.468 9.275 19.962 9.545 ;
     RECT  0.036 8.971 0.234 9.553 ;
     RECT  14.652 9.239 16.254 9.625 ;
     RECT  14.508 9.625 16.254 9.689 ;
     RECT  13.032 8.735 13.497 9.787 ;
     RECT  13.032 9.787 13.698 9.895 ;
     RECT  14.508 9.689 15.066 9.923 ;
     RECT  12.096 9.925 12.114 9.931 ;
     RECT  12.924 9.895 13.698 9.931 ;
     RECT  12.096 9.931 13.878 9.965 ;
     RECT  12.24 9.965 13.878 10.049 ;
     RECT  18.504 9.545 19.962 10.121 ;
     RECT  12.24 10.049 12.258 10.229 ;
     RECT  15.915 9.689 16.254 10.327 ;
     RECT  15.915 10.327 16.758 10.399 ;
     RECT  14.652 9.923 15.066 10.435 ;
     RECT  15.915 10.399 17.442 10.435 ;
     RECT  14.652 10.435 17.73 10.471 ;
     RECT  18.504 10.121 18.897 10.471 ;
     RECT  14.652 10.471 18.897 10.697 ;
     RECT  13.032 10.049 13.878 10.831 ;
     RECT  19.944 10.121 19.962 10.843 ;
     RECT  13.032 10.831 13.914 10.939 ;
     RECT  14.652 10.697 17.586 10.939 ;
     RECT  13.032 10.939 17.586 11.003 ;
     RECT  19.944 10.843 20.538 11.003 ;
     RECT  13.032 11.003 16.326 11.039 ;
     RECT  1.728 9.275 8.097 11.201 ;
     RECT  13.032 11.039 16.254 11.201 ;
     RECT  12.24 11.137 12.258 11.399 ;
     RECT  13.032 11.201 14.058 11.399 ;
     RECT  13.032 11.399 13.914 11.435 ;
     RECT  13.032 11.435 13.734 11.515 ;
     RECT  18.36 10.697 18.897 11.551 ;
     RECT  19.944 11.003 19.962 11.551 ;
     RECT  12.924 11.515 13.734 11.579 ;
     RECT  17.1 11.003 17.586 11.641 ;
     RECT  18.36 11.551 19.962 11.641 ;
     RECT  12.924 11.579 13.698 11.669 ;
     RECT  15.156 11.201 16.254 11.821 ;
     RECT  17.1 11.641 19.962 11.821 ;
     RECT  15.156 11.821 19.962 11.939 ;
     RECT  18.396 11.939 19.962 11.975 ;
     RECT  15.156 11.939 17.658 12.083 ;
     RECT  0.036 9.553 0.342 12.091 ;
     RECT  17.172 12.083 17.442 12.209 ;
     RECT  0.036 12.091 0.414 12.269 ;
     RECT  17.244 12.209 17.442 12.281 ;
     RECT  17.424 12.281 17.442 12.317 ;
     RECT  13.032 11.669 13.698 12.325 ;
     RECT  15.156 12.083 16.29 12.325 ;
     RECT  0.036 12.269 0.378 12.509 ;
     RECT  13.032 12.325 16.29 12.551 ;
     RECT  18.615 11.975 19.962 12.551 ;
     RECT  1.98 11.201 8.097 12.619 ;
     RECT  12.096 11.419 12.114 12.749 ;
     RECT  13.032 12.551 13.497 12.757 ;
     RECT  14.256 12.551 16.29 12.785 ;
     RECT  12.888 12.757 13.497 12.901 ;
     RECT  14.256 12.785 14.85 12.929 ;
     RECT  12.24 12.901 13.497 13.019 ;
     RECT  12.888 13.019 13.497 13.055 ;
     RECT  14.436 12.929 14.85 13.085 ;
     RECT  18.615 12.551 19.026 13.091 ;
     RECT  0.036 12.509 0.342 13.277 ;
     RECT  14.436 13.085 14.778 13.325 ;
     RECT  17.424 13.405 17.658 13.441 ;
     RECT  18.615 13.091 18.897 13.441 ;
     RECT  17.424 13.441 18.897 13.559 ;
     RECT  0.072 13.277 0.342 13.631 ;
     RECT  17.424 13.559 17.658 13.639 ;
     RECT  14.76 13.325 14.778 13.661 ;
     RECT  15.915 12.785 16.29 13.675 ;
     RECT  17.1 13.639 17.658 13.675 ;
     RECT  15.915 13.675 17.658 13.703 ;
     RECT  18.54 13.559 18.897 13.865 ;
     RECT  0.108 13.631 0.342 13.901 ;
     RECT  15.915 13.703 17.298 13.909 ;
     RECT  15.3 13.909 17.298 14.099 ;
     RECT  1.404 12.619 8.097 14.237 ;
     RECT  14.544 14.215 14.562 14.251 ;
     RECT  13.032 13.055 13.497 14.377 ;
     RECT  14.328 14.251 14.562 14.413 ;
     RECT  0.108 13.901 0.306 14.449 ;
     RECT  12.888 14.377 13.497 14.449 ;
     RECT  14.256 14.413 14.562 14.449 ;
     RECT  12.024 14.449 12.042 14.521 ;
     RECT  12.888 14.449 14.562 14.521 ;
     RECT  12.024 14.521 14.994 14.675 ;
     RECT  10.515 2.795 10.797 14.683 ;
     RECT  0.036 14.449 0.306 14.719 ;
     RECT  18.576 13.865 18.897 14.755 ;
     RECT  10.515 14.683 10.854 14.783 ;
     RECT  12.024 14.675 12.258 14.819 ;
     RECT  15.915 14.099 17.298 14.917 ;
     RECT  18.252 14.755 18.897 14.917 ;
     RECT  13.032 14.675 14.994 15.025 ;
     RECT  15.915 14.917 18.897 15.025 ;
     RECT  2.34 14.237 8.097 15.053 ;
     RECT  13.032 15.025 18.897 15.287 ;
     RECT  13.032 15.287 17.658 15.359 ;
     RECT  0.036 14.719 0.558 15.437 ;
     RECT  2.34 15.053 7.002 15.449 ;
     RECT  17.172 15.359 17.658 15.449 ;
     RECT  18.615 15.287 18.897 15.451 ;
     RECT  19.944 12.551 19.962 15.451 ;
     RECT  17.64 15.449 17.658 15.521 ;
     RECT  13.032 15.359 16.29 15.529 ;
     RECT  2.34 15.449 6.93 15.565 ;
     RECT  2.304 15.565 6.93 15.719 ;
     RECT  12.96 15.529 16.29 15.719 ;
     RECT  12.024 14.819 12.186 15.835 ;
     RECT  12.96 15.719 14.562 15.835 ;
     RECT  12.024 15.835 14.562 15.863 ;
     RECT  18.615 15.451 19.962 15.863 ;
     RECT  12.024 15.863 14.31 15.965 ;
     RECT  12.744 15.965 14.31 15.989 ;
     RECT  18.615 15.863 18.99 16.025 ;
     RECT  0.036 15.437 0.522 16.231 ;
     RECT  17.208 16.231 17.226 16.267 ;
     RECT  18.615 16.025 18.897 16.267 ;
     RECT  17.208 16.267 18.897 16.303 ;
     RECT  15.372 15.719 16.29 16.375 ;
     RECT  17.172 16.303 18.897 16.375 ;
     RECT  2.376 15.719 6.93 16.411 ;
     RECT  7.815 15.053 8.097 16.411 ;
     RECT  11.844 16.033 11.862 16.411 ;
     RECT  15.372 16.375 18.897 16.459 ;
     RECT  11.736 16.411 11.862 16.529 ;
     RECT  15.336 16.459 18.897 16.529 ;
     RECT  2.376 16.411 8.097 16.565 ;
     RECT  15.915 16.529 18.897 16.565 ;
     RECT  12.96 15.989 14.31 16.681 ;
     RECT  15.915 16.565 17.442 16.709 ;
     RECT  2.376 16.565 6.93 16.799 ;
     RECT  1.404 14.237 1.53 16.829 ;
     RECT  2.412 16.799 6.93 16.835 ;
     RECT  18.216 16.565 18.897 16.871 ;
     RECT  1.404 16.829 1.458 16.973 ;
     RECT  0.036 16.231 0.558 16.987 ;
     RECT  1.404 16.973 1.422 16.987 ;
     RECT  12.96 16.681 15.138 17.069 ;
     RECT  14.544 17.069 15.138 17.105 ;
     RECT  15.915 16.709 17.298 17.105 ;
     RECT  0.036 16.987 1.422 17.117 ;
     RECT  12.96 17.069 13.698 17.117 ;
     RECT  12.96 17.117 13.626 17.149 ;
     RECT  2.412 16.835 6.858 17.339 ;
     RECT  12.24 17.149 13.626 17.339 ;
     RECT  0.036 17.117 0.558 17.405 ;
     RECT  12.06 17.371 12.078 17.411 ;
     RECT  15.12 17.105 15.138 17.455 ;
     RECT  15.915 17.105 16.902 17.455 ;
     RECT  12.924 17.339 13.626 17.609 ;
     RECT  12.96 17.609 13.626 17.651 ;
     RECT  7.815 16.565 8.097 17.725 ;
     RECT  7.74 17.725 8.097 17.761 ;
     RECT  17.64 17.491 17.73 17.761 ;
     RECT  18.615 16.871 18.897 17.761 ;
     RECT  7.704 17.761 8.097 17.879 ;
     RECT  15.12 17.455 16.902 17.959 ;
     RECT  17.64 17.761 18.897 17.959 ;
     RECT  7.74 17.879 8.097 17.987 ;
     RECT  2.412 17.339 6.678 18.031 ;
     RECT  2.304 18.031 6.678 18.193 ;
     RECT  15.12 17.959 18.897 18.235 ;
     RECT  19.944 15.863 19.962 18.235 ;
     RECT  14.256 18.265 14.274 18.301 ;
     RECT  15.12 18.235 19.962 18.301 ;
     RECT  0.216 17.405 0.558 18.365 ;
     RECT  12.96 17.651 13.497 18.427 ;
     RECT  14.256 18.301 19.962 18.427 ;
     RECT  12.96 18.427 19.962 18.463 ;
     RECT  0.252 18.365 0.558 18.509 ;
     RECT  2.304 18.193 6.858 18.535 ;
     RECT  12.24 18.463 19.962 18.563 ;
     RECT  12.24 18.563 18.954 18.667 ;
     RECT  12.06 18.667 18.954 18.689 ;
     RECT  15.156 18.689 18.954 18.725 ;
     RECT  15.372 18.725 18.954 18.761 ;
     RECT  12.06 18.689 12.078 18.797 ;
     RECT  12.888 18.689 13.878 18.797 ;
     RECT  12.888 18.797 13.698 18.869 ;
     RECT  12.888 18.869 13.497 18.995 ;
     RECT  2.304 18.535 6.894 19.111 ;
     RECT  2.304 19.111 6.966 19.201 ;
     RECT  0.288 18.509 0.558 19.229 ;
     RECT  15.372 18.761 18.897 19.229 ;
     RECT  15.372 19.229 17.694 19.265 ;
     RECT  2.304 19.201 7.038 19.499 ;
     RECT  15.372 19.265 17.442 19.499 ;
     RECT  2.304 19.499 6.894 19.535 ;
     RECT  18.504 19.229 18.897 19.535 ;
     RECT  18.615 19.535 18.897 19.543 ;
     RECT  6.804 19.535 6.894 19.565 ;
     RECT  17.1 19.499 17.442 19.607 ;
     RECT  15.372 19.499 16.197 19.651 ;
     RECT  2.304 19.535 5.85 19.769 ;
     RECT  15.336 19.651 16.197 19.777 ;
     RECT  18.615 19.543 19.026 19.841 ;
     RECT  14.832 19.777 16.197 19.885 ;
     RECT  18.615 19.841 18.954 19.913 ;
     RECT  2.304 19.769 5.706 19.949 ;
     RECT  0.54 19.229 0.558 20.011 ;
     RECT  13.032 18.995 13.497 20.059 ;
     RECT  12.06 20.059 12.078 20.111 ;
     RECT  13.032 20.059 13.698 20.119 ;
     RECT  14.508 19.885 16.197 20.119 ;
     RECT  13.032 20.119 16.197 20.155 ;
     RECT  12.924 20.155 16.197 20.191 ;
     RECT  6.804 19.565 6.858 20.219 ;
     RECT  0.216 20.011 0.558 20.237 ;
     RECT  17.424 19.607 17.442 20.281 ;
     RECT  12.24 20.191 16.197 20.309 ;
     RECT  17.424 20.281 17.658 20.461 ;
     RECT  2.34 19.949 5.706 20.489 ;
     RECT  18.615 19.913 18.897 20.551 ;
     RECT  0.54 20.237 0.558 20.573 ;
     RECT  3.636 20.489 5.706 20.579 ;
     RECT  13.032 20.309 16.197 20.683 ;
     RECT  17.208 20.461 17.658 20.683 ;
     RECT  6.84 20.219 6.858 20.731 ;
     RECT  13.032 20.683 17.658 20.731 ;
     RECT  18.54 20.551 18.897 20.731 ;
     RECT  6.84 20.731 6.894 20.858 ;
     RECT  13.032 20.731 18.897 20.885 ;
     RECT  6.84 20.858 6.858 20.957 ;
     RECT  17.208 20.885 18.897 20.957 ;
     RECT  17.208 20.957 17.442 20.993 ;
     RECT  2.34 20.489 2.862 21.001 ;
     RECT  19.944 18.563 19.962 21.067 ;
     RECT  3.636 20.579 5.397 21.119 ;
     RECT  17.208 20.993 17.334 21.119 ;
     RECT  17.208 21.119 17.226 21.155 ;
     RECT  2.304 21.001 2.862 21.235 ;
     RECT  3.636 21.119 3.726 21.235 ;
     RECT  19.944 21.067 20.538 21.263 ;
     RECT  12.24 20.309 12.258 21.355 ;
     RECT  2.304 21.235 3.726 21.389 ;
     RECT  4.5 21.119 5.397 21.389 ;
     RECT  12.096 21.355 12.258 21.389 ;
     RECT  12.096 21.389 12.114 21.395 ;
     RECT  13.032 20.885 16.197 21.397 ;
     RECT  12.888 21.397 16.197 21.461 ;
     RECT  19.944 21.263 19.962 21.461 ;
     RECT  14.832 21.461 16.197 21.569 ;
     RECT  1.404 17.117 1.422 21.659 ;
     RECT  4.536 21.389 5.397 21.659 ;
     RECT  12.888 21.461 14.058 21.659 ;
     RECT  15.228 21.569 16.197 21.659 ;
     RECT  12.888 21.659 13.914 21.695 ;
     RECT  15.876 21.659 16.197 21.731 ;
     RECT  4.608 21.659 5.397 22.001 ;
     RECT  2.304 21.389 3.654 22.199 ;
     RECT  2.304 22.199 2.862 22.469 ;
     RECT  3.744 22.351 3.762 22.505 ;
     RECT  2.304 22.469 2.697 22.577 ;
     RECT  2.415 22.577 2.697 23.507 ;
     RECT  5.115 22.001 5.397 23.507 ;
     RECT  7.815 17.987 8.097 23.507 ;
     RECT  10.515 14.783 10.797 23.507 ;
     RECT  13.215 21.695 13.497 23.507 ;
     RECT  15.915 21.731 16.197 23.507 ;
     RECT  18.615 20.957 18.897 23.507 ;
     RECT  2.415 23.507 2.505 23.777 ;
     RECT  5.115 23.507 5.205 23.777 ;
     RECT  7.815 23.507 7.905 23.777 ;
     RECT  10.515 23.507 10.605 23.777 ;
     RECT  13.215 23.507 13.305 23.777 ;
     RECT  15.915 23.507 16.005 23.777 ;
     RECT  18.615 23.507 18.705 23.777 ;
    LAYER M4 ;
     RECT  0.025 13.248 0.133 13.272 ;
     RECT  0.133 13.248 0.156 13.464 ;
     RECT  0.025 17.376 0.156 17.4 ;
     RECT  0.156 4.512 0.245 21.432 ;
     RECT  0.245 4.704 0.353 21.432 ;
     RECT  0.353 4.704 0.569 13.176 ;
     RECT  0.569 4.896 2.408 13.176 ;
     RECT  0.353 14.208 2.408 21.432 ;
     RECT  2.408 2.148 2.512 23.772 ;
     RECT  2.512 2.418 2.704 23.502 ;
     RECT  2.704 14.448 2.867 20.904 ;
     RECT  2.867 17.088 2.909 20.904 ;
     RECT  2.909 17.136 3.413 20.904 ;
     RECT  2.704 4.896 5.108 13.08 ;
     RECT  2.867 14.448 5.108 16.104 ;
     RECT  3.413 17.136 5.108 17.16 ;
     RECT  3.413 18.144 5.108 20.904 ;
     RECT  5.108 2.148 5.212 23.772 ;
     RECT  5.212 2.418 5.404 23.502 ;
     RECT  5.404 6.576 5.573 7.752 ;
     RECT  5.404 8.832 5.645 10.92 ;
     RECT  5.645 10.176 5.681 10.92 ;
     RECT  5.573 7.632 5.699 7.752 ;
     RECT  5.699 7.728 5.753 7.752 ;
     RECT  5.645 8.832 5.753 8.856 ;
     RECT  5.404 12.336 5.789 13.08 ;
     RECT  5.573 6.576 7.808 6.6 ;
     RECT  5.681 10.896 7.808 10.92 ;
     RECT  5.789 13.056 7.808 13.08 ;
     RECT  5.404 14.448 7.808 15.24 ;
     RECT  5.404 19.536 7.808 19.56 ;
     RECT  7.808 2.148 7.912 23.772 ;
     RECT  7.912 2.418 8.104 23.502 ;
     RECT  8.104 13.056 10.508 13.08 ;
     RECT  10.508 2.148 10.612 23.772 ;
     RECT  10.612 2.148 10.748 23.502 ;
     RECT  10.748 1.728 10.804 23.502 ;
     RECT  10.804 1.728 10.835 1.752 ;
     RECT  12.037 18.672 12.049 18.696 ;
     RECT  12.044 9.936 12.085 9.96 ;
     RECT  12.049 18.672 12.085 18.792 ;
     RECT  12.013 15.936 12.097 15.96 ;
     RECT  12.037 17.376 12.124 17.4 ;
     RECT  12.085 18.672 12.124 18.984 ;
     RECT  12.044 7.248 12.131 7.272 ;
     RECT  12.044 8.4 12.131 8.424 ;
     RECT  12.085 9.6 12.131 9.96 ;
     RECT  12.044 20.064 12.131 20.088 ;
     RECT  12.044 21.36 12.131 21.384 ;
     RECT  12.124 18.768 12.133 18.984 ;
     RECT  12.085 11.424 12.169 11.448 ;
     RECT  12.131 9.6 13.129 9.624 ;
     RECT  12.013 5.568 13.208 5.592 ;
     RECT  13.129 9.36 13.208 9.624 ;
     RECT  10.804 13.056 13.208 13.08 ;
     RECT  12.133 18.96 13.208 18.984 ;
     RECT  13.208 2.148 13.312 23.772 ;
     RECT  13.312 2.418 13.504 23.502 ;
     RECT  13.504 5.568 13.709 5.592 ;
     RECT  13.504 17.088 13.709 18.984 ;
     RECT  13.709 17.52 13.715 18.984 ;
     RECT  13.504 20.064 13.715 20.088 ;
     RECT  13.504 21.36 13.756 21.384 ;
     RECT  13.504 6.816 13.763 6.84 ;
     RECT  13.504 8.4 13.763 9.816 ;
     RECT  13.504 13.056 14.725 13.08 ;
     RECT  14.725 12.96 14.732 13.08 ;
     RECT  13.763 9.36 14.773 9.384 ;
     RECT  14.773 8.784 14.819 9.384 ;
     RECT  14.732 12.864 14.861 13.656 ;
     RECT  14.861 13.056 15.26 13.656 ;
     RECT  13.715 17.616 15.26 17.64 ;
     RECT  14.819 8.784 15.301 9.288 ;
     RECT  15.26 13.056 15.301 13.944 ;
     RECT  15.301 5.088 15.325 5.112 ;
     RECT  15.301 10.416 15.325 10.584 ;
     RECT  15.26 7.632 15.541 7.656 ;
     RECT  15.301 8.64 15.541 9.288 ;
     RECT  15.325 4.992 15.908 5.112 ;
     RECT  15.301 6.24 15.908 6.264 ;
     RECT  15.541 7.632 15.908 9.288 ;
     RECT  15.325 10.416 15.908 10.824 ;
     RECT  15.289 12.048 15.908 12.072 ;
     RECT  15.301 13.056 15.908 14.232 ;
     RECT  15.26 15.216 15.908 15.24 ;
     RECT  15.301 16.464 15.908 16.488 ;
     RECT  15.26 17.616 15.908 17.928 ;
     RECT  15.301 19.68 15.908 19.704 ;
     RECT  15.253 20.688 15.908 20.712 ;
     RECT  15.908 2.148 16.012 23.772 ;
     RECT  16.012 2.418 16.204 23.502 ;
     RECT  16.204 10.416 16.661 10.728 ;
     RECT  16.204 4.992 16.913 5.016 ;
     RECT  16.661 10.416 16.913 10.44 ;
     RECT  16.204 12.048 16.913 12.072 ;
     RECT  16.204 14.208 16.913 14.232 ;
     RECT  16.204 17.088 16.913 17.688 ;
     RECT  16.204 20.688 16.913 20.712 ;
     RECT  16.204 7.776 16.924 8.568 ;
     RECT  16.924 8.544 16.944 8.568 ;
     RECT  16.204 13.056 18.608 13.08 ;
     RECT  18.608 2.148 18.712 23.772 ;
     RECT  18.712 2.418 18.904 23.502 ;
     RECT  18.904 5.232 19.933 5.256 ;
     RECT  18.904 6.624 19.933 6.648 ;
     RECT  18.904 8.064 19.933 8.088 ;
     RECT  18.904 9.456 19.933 9.48 ;
     RECT  18.904 12.288 19.933 12.984 ;
     RECT  18.904 14.016 19.933 14.04 ;
     RECT  18.904 15.456 19.933 15.48 ;
     RECT  18.904 18.24 19.933 18.264 ;
     RECT  18.904 19.632 19.933 19.656 ;
     RECT  19.933 4.512 21.42 21.432 ;
    LAYER M5 ;
     RECT  10.8 0.144 10.824 1.763 ;
     RECT  10.8 1.763 10.812 2.137 ;
     RECT  2.4 2.137 2.52 2.151 ;
     RECT  5.1 2.137 5.22 2.151 ;
     RECT  7.8 2.137 7.92 2.151 ;
     RECT  13.2 2.137 13.32 2.151 ;
     RECT  15.9 2.137 16.02 2.151 ;
     RECT  18.6 2.137 18.72 2.151 ;
     RECT  15.9 2.151 16.212 5.077 ;
     RECT  13.2 2.151 13.512 6.805 ;
     RECT  5.1 2.151 5.412 7.621 ;
     RECT  5.1 7.621 5.688 7.763 ;
     RECT  15.312 5.077 16.212 7.765 ;
     RECT  15.312 7.765 16.872 8.579 ;
     RECT  15.312 8.579 16.212 8.773 ;
     RECT  2.4 2.151 2.712 8.965 ;
     RECT  13.2 6.805 13.752 9.827 ;
     RECT  12.096 7.237 12.12 11.459 ;
     RECT  14.784 8.773 16.212 12.083 ;
     RECT  14.784 12.083 14.808 12.949 ;
     RECT  14.736 12.949 14.808 13.091 ;
     RECT  14.784 13.091 14.808 13.909 ;
     RECT  15.9 12.083 16.212 13.909 ;
     RECT  2.4 8.965 2.856 14.773 ;
     RECT  2.4 14.773 3.432 14.963 ;
     RECT  2.4 14.963 2.856 16.595 ;
     RECT  0.288 16.981 0.312 17.315 ;
     RECT  13.2 9.827 13.512 17.509 ;
     RECT  14.784 13.909 16.212 17.651 ;
     RECT  12.048 15.925 12.072 18.707 ;
     RECT  15.312 17.651 16.212 20.723 ;
     RECT  12.096 18.757 12.12 21.395 ;
     RECT  13.2 17.509 13.704 21.395 ;
     RECT  2.4 16.595 2.712 23.769 ;
     RECT  5.1 7.763 5.412 23.769 ;
     RECT  7.8 2.151 8.112 23.769 ;
     RECT  10.5 2.137 10.812 23.769 ;
     RECT  13.2 21.395 13.512 23.769 ;
     RECT  15.9 20.723 16.212 23.769 ;
     RECT  18.6 2.151 18.912 23.769 ;
     RECT  2.4 23.769 2.52 23.783 ;
     RECT  5.1 23.769 5.22 23.783 ;
     RECT  7.8 23.769 7.92 23.783 ;
     RECT  10.5 23.769 10.62 23.783 ;
     RECT  13.2 23.769 13.32 23.783 ;
     RECT  15.9 23.769 16.02 23.783 ;
     RECT  18.6 23.769 18.72 23.783 ;
  END
END hbfd_rly_48_EW_fc_f2
END LIBRARY
